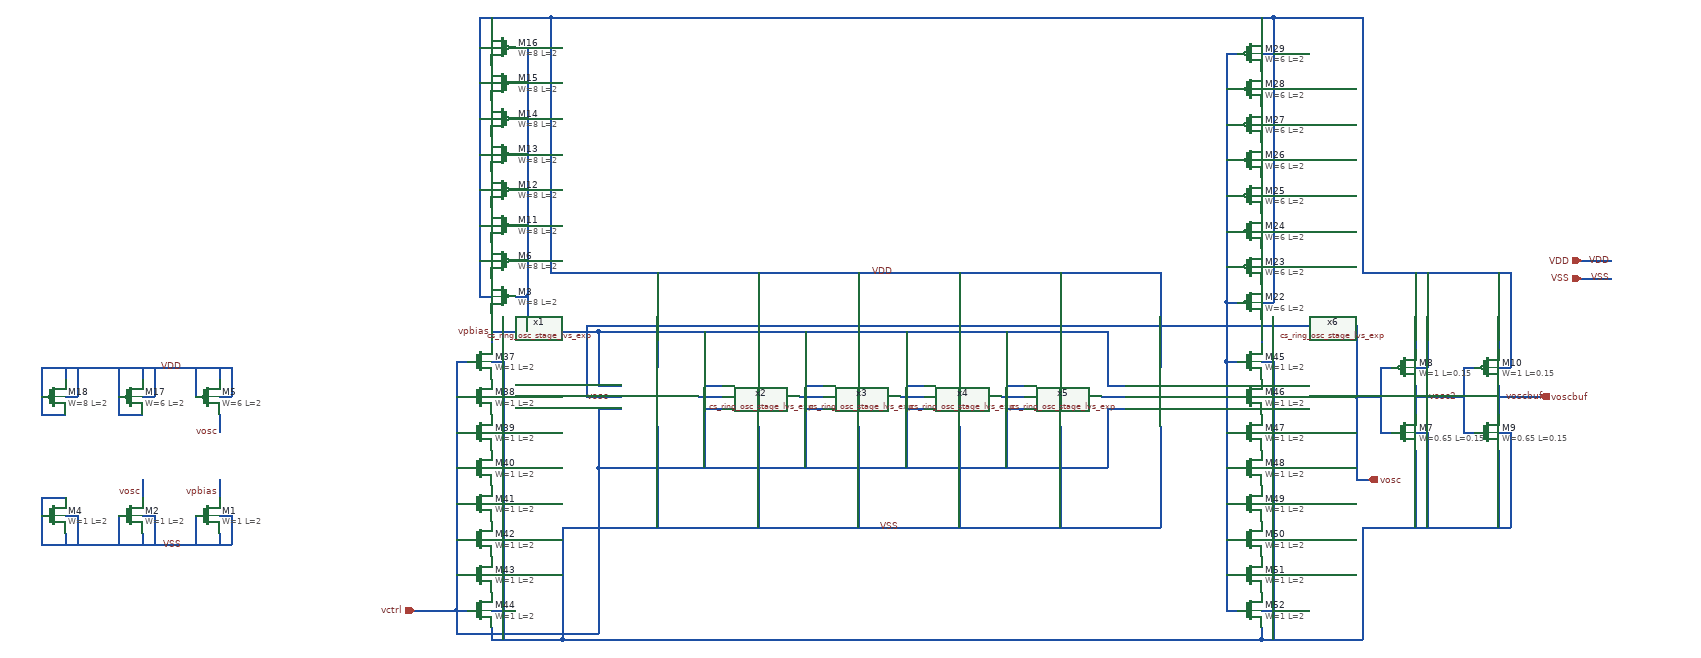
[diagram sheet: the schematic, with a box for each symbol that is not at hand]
v {xschem version=2.9.9 file_version=1.2 

* Copyright 2020 Stefan Frederik Schippers
* 
* Licensed under the Apache License, Version 2.0 (the "License");
* you may not use this file except in compliance with the License.
* You may obtain a copy of the License at
*
*     https://www.apache.org/licenses/LICENSE-2.0
*
* Unless required by applicable law or agreed to in writing, software
* distributed under the License is distributed on an "AS IS" BASIS,
* WITHOUT WARRANTIES OR CONDITIONS OF ANY KIND, either express or implied.
* See the License for the specific language governing permissions and
* limitations under the License.

}
G {}
K {}
V {}
S {}
E {}
N 100 -140 170 -140 { lab=vctrl}
N 350 -610 410 -610 { lab=vpbias}
N 410 -610 410 -520 { lab=vpbias}
N 410 -520 450 -520 { lab=vpbias}
N 410 -480 410 -380 { lab=vctrl}
N 410 -480 450 -480 { lab=vctrl}
N 580 -500 620 -500 { lab=#net1}
N 750 -500 790 -500 { lab=#net2}
N 920 -500 960 -500 { lab=#net3}
N 1090 -500 1130 -500 { lab=#net4}
N 1260 -500 1300 -500 { lab=#net5}
N 1430 -500 1470 -500 { lab=#net6}
N 410 -610 1270 -610 { lab=vpbias}
N 1270 -520 1300 -520 { lab=vpbias}
N 410 -380 1270 -380 { lab=vctrl}
N 1270 -480 1300 -480 { lab=vctrl}
N 1100 -520 1130 -520 { lab=vpbias}
N 1100 -480 1130 -480 { lab=vctrl}
N 930 -520 960 -520 { lab=vpbias}
N 930 -480 960 -480 { lab=vctrl}
N 760 -480 790 -480 { lab=vctrl}
N 760 -520 790 -520 { lab=vpbias}
N 590 -520 620 -520 { lab=vpbias}
N 590 -610 590 -520 { lab=vpbias}
N 590 -480 620 -480 { lab=vctrl}
N 590 -480 590 -380 { lab=vctrl}
N 390 -500 450 -500 { lab=vosc}
N 1690 -500 1690 -360 { lab=vosc}
N 1790 -550 1810 -550 { lab=VDD}
N 1790 -520 1790 -470 { lab=vosc2}
N 1790 -440 1810 -440 { lab=VSS}
N 1730 -550 1730 -490 { lab=vosc}
N 1730 -550 1750 -550 { lab=vosc}
N 1730 -490 1730 -440 { lab=vosc}
N 1730 -440 1750 -440 { lab=vosc}
N 1790 -710 1790 -580 { lab=VDD}
N 1810 -710 1810 -550 { lab=VDD}
N 1790 -410 1790 -280 { lab=VSS}
N 1810 -440 1810 -280 { lab=VSS}
N 1930 -550 1950 -550 { lab=VDD}
N 1930 -520 1930 -470 { lab=voscbuf}
N 1930 -440 1950 -440 { lab=VSS}
N 1870 -550 1870 -490 { lab=vosc2}
N 1870 -550 1890 -550 { lab=vosc2}
N 1870 -490 1870 -440 { lab=vosc2}
N 1870 -440 1890 -440 { lab=vosc2}
N 1930 -710 1930 -580 { lab=VDD}
N 1950 -710 1950 -550 { lab=VDD}
N 1930 -410 1930 -280 { lab=VSS}
N 1950 -440 1950 -280 { lab=VSS}
N 1790 -500 1870 -500 { lab=vosc2}
N 1690 -500 1730 -500 { lab=vosc}
N 510 -710 510 -550 { lab=VDD}
N 510 -450 510 -280 { lab=VSS}
N 760 -610 760 -520 { lab=vpbias}
N 760 -480 760 -380 { lab=vctrl}
N 680 -710 680 -550 { lab=VDD}
N 680 -450 680 -280 { lab=VSS}
N 930 -610 930 -520 { lab=vpbias}
N 930 -480 930 -380 { lab=vctrl}
N 850 -710 850 -550 { lab=VDD}
N 850 -450 850 -280 { lab=VSS}
N 1100 -610 1100 -520 { lab=vpbias}
N 1100 -480 1100 -380 { lab=vctrl}
N 1020 -710 1020 -550 { lab=VDD}
N 1020 -450 1020 -280 { lab=VSS}
N 1270 -610 1270 -520 { lab=vpbias}
N 1270 -480 1270 -380 { lab=vctrl}
N 1190 -710 1190 -550 { lab=VDD}
N 1190 -450 1190 -280 { lab=VSS}
N 1360 -710 1360 -550 { lab=VDD}
N 1360 -450 1360 -280 { lab=VSS}
N 2070 -730 2120 -730 { lab=VDD}
N 2070 -700 2120 -700 { lab=VSS}
N 1930 -500 2000 -500 { lab=voscbuf}
N 1690 -360 1710 -360 { lab=vosc}
N 210 -670 230 -670 { lab=VDD}
N 230 -1140 230 -1120 { lab=VDD}
N 210 -730 230 -730 { lab=VDD}
N 210 -790 230 -790 { lab=VDD}
N 210 -850 230 -850 { lab=VDD}
N 210 -910 230 -910 { lab=VDD}
N 210 -970 230 -970 { lab=VDD}
N 210 -1030 230 -1030 { lab=VDD}
N 210 -1090 230 -1090 { lab=VDD}
N 270 -1090 290 -1090 { lab=vpbias}
N 290 -1090 290 -670 { lab=vpbias}
N 270 -670 290 -670 { lab=vpbias}
N 270 -730 290 -730 { lab=vpbias}
N 270 -790 290 -790 { lab=vpbias}
N 270 -850 290 -850 { lab=vpbias}
N 270 -910 290 -910 { lab=vpbias}
N 270 -970 290 -970 { lab=vpbias}
N 270 -1030 290 -1030 { lab=vpbias}
N 230 -110 230 -90 { lab=VSS}
N 230 -560 250 -560 { lab=VSS}
N 230 -500 250 -500 { lab=VSS}
N 230 -440 250 -440 { lab=VSS}
N 230 -380 250 -380 { lab=VSS}
N 230 -320 250 -320 { lab=VSS}
N 230 -260 250 -260 { lab=VSS}
N 230 -200 250 -200 { lab=VSS}
N 230 -140 250 -140 { lab=VSS}
N 170 -560 190 -560 { lab=vctrl}
N 170 -560 170 -140 { lab=vctrl}
N 170 -140 190 -140 { lab=vctrl}
N 170 -200 190 -200 { lab=vctrl}
N 170 -260 190 -260 { lab=vctrl}
N 170 -320 190 -320 { lab=vctrl}
N 170 -380 190 -380 { lab=vctrl}
N 170 -440 190 -440 { lab=vctrl}
N 170 -500 190 -500 { lab=vctrl}
N 250 -560 250 -90 { lab=VSS}
N 230 -640 230 -590 { lab=vpbias}
N 230 -90 350 -90 { lab=VSS}
N 350 -280 350 -90 { lab=VSS}
N 410 -380 410 -100 { lab=vctrl}
N 170 -100 410 -100 { lab=vctrl}
N 170 -140 170 -100 { lab=vctrl}
N 230 -610 350 -610 { lab=vpbias}
N 210 -1140 210 -670 { lab=VDD}
N 210 -1140 330 -1140 { lab=VDD}
N 330 -1140 330 -710 { lab=VDD}
N 1530 -660 1550 -660 { lab=VDD}
N 1530 -720 1550 -720 { lab=VDD}
N 1530 -780 1550 -780 { lab=VDD}
N 1530 -840 1550 -840 { lab=VDD}
N 1530 -900 1550 -900 { lab=VDD}
N 1530 -960 1550 -960 { lab=VDD}
N 1530 -1020 1550 -1020 { lab=VDD}
N 1530 -1080 1550 -1080 { lab=VDD}
N 1530 -560 1550 -560 { lab=VSS}
N 1530 -500 1550 -500 { lab=VSS}
N 1530 -440 1550 -440 { lab=VSS}
N 1530 -380 1550 -380 { lab=VSS}
N 1530 -320 1550 -320 { lab=VSS}
N 1530 -260 1550 -260 { lab=VSS}
N 1530 -200 1550 -200 { lab=VSS}
N 1530 -140 1550 -140 { lab=VSS}
N 1530 -630 1530 -590 { lab=vosc}
N 1470 -560 1490 -560 { lab=#net6}
N 1470 -140 1490 -140 { lab=#net6}
N 1470 -200 1490 -200 { lab=#net6}
N 1470 -260 1490 -260 { lab=#net6}
N 1470 -320 1490 -320 { lab=#net6}
N 1470 -380 1490 -380 { lab=#net6}
N 1470 -440 1490 -440 { lab=#net6}
N 1470 -500 1490 -500 { lab=#net6}
N 1470 -1080 1490 -1080 { lab=#net6}
N 1470 -1080 1470 -660 { lab=#net6}
N 1470 -660 1490 -660 { lab=#net6}
N 1470 -720 1490 -720 { lab=#net6}
N 1470 -780 1490 -780 { lab=#net6}
N 1470 -840 1490 -840 { lab=#net6}
N 1470 -900 1490 -900 { lab=#net6}
N 1470 -960 1490 -960 { lab=#net6}
N 1470 -1020 1490 -1020 { lab=#net6}
N 1470 -560 1470 -140 { lab=#net6}
N 350 -90 1530 -90 { lab=VSS}
N 1530 -110 1530 -90 { lab=VSS}
N 1550 -560 1550 -90 { lab=VSS}
N 350 -280 1360 -280 { lab=VSS}
N 330 -710 1360 -710 { lab=VDD}
N 1530 -1130 1530 -1110 { lab=VDD}
N 1470 -660 1470 -560 { lab=#net6}
N 1690 -610 1690 -500 { lab=vosc}
N 330 -1140 1550 -1140 { lab=VDD}
N 1550 -1140 1550 -1120 { lab=VDD}
N 1550 -1120 1550 -660 { lab=VDD}
N 1530 -1140 1530 -1130 { lab=VDD}
N 1550 -1140 1700 -1140 { lab=VDD}
N 1700 -1140 1700 -710 { lab=VDD}
N 1700 -710 1950 -710 { lab=VDD}
N 1530 -90 1700 -90 { lab=VSS}
N 1700 -280 1700 -90 { lab=VSS}
N 1700 -280 1950 -280 { lab=VSS}
N 290 -670 290 -610 { lab=vpbias}
N 1690 -620 1690 -610 { lab=vosc}
N 1530 -620 1690 -620 { lab=vosc}
N 390 -620 1530 -620 { lab=vosc}
N 390 -620 390 -500 { lab=vosc}
N -230 -300 -210 -300 { lab=VSS}
N -210 -300 -210 -250 { lab=VSS}
N -230 -270 -230 -250 { lab=VSS}
N -270 -300 -270 -250 { lab=VSS}
N -230 -360 -230 -330 { lab=vpbias}
N -360 -300 -340 -300 { lab=VSS}
N -340 -300 -340 -250 { lab=VSS}
N -360 -270 -360 -250 { lab=VSS}
N -400 -300 -400 -250 { lab=VSS}
N -360 -360 -360 -330 { lab=vosc}
N -490 -300 -470 -300 { lab=VSS}
N -470 -300 -470 -250 { lab=VSS}
N -490 -270 -490 -250 { lab=VSS}
N -530 -300 -530 -250 { lab=VSS}
N -530 -250 -210 -250 { lab=VSS}
N -230 -470 -230 -440 { lab=vosc}
N -230 -550 -230 -530 { lab=#net7}
N -230 -500 -210 -500 { lab=#net7}
N -210 -550 -210 -500 { lab=#net7}
N -270 -550 -270 -500 { lab=#net7}
N -360 -550 -360 -530 { lab=#net7}
N -360 -500 -340 -500 { lab=#net7}
N -340 -550 -340 -500 { lab=#net7}
N -400 -550 -400 -500 { lab=#net7}
N -400 -470 -360 -470 { lab=#net7}
N -400 -500 -400 -470 { lab=#net7}
N -530 -330 -490 -330 { lab=VSS}
N -530 -330 -530 -300 { lab=VSS}
N -490 -550 -490 -530 { lab=#net7}
N -490 -500 -470 -500 { lab=#net7}
N -470 -550 -470 -500 { lab=#net7}
N -530 -550 -530 -500 { lab=#net7}
N -530 -470 -490 -470 { lab=#net7}
N -530 -500 -530 -470 { lab=#net7}
N -530 -550 -210 -550 { lab=#net7}
C {devices/title.sym} 160 -30 0 0 {name=l1 author="Nikhil Poole"}
C {devices/lab_wire.sym} 430 -500 0 0 {name=l9 sig_type=std_logic lab=vosc}
C {devices/lab_wire.sym} 230 -610 0 0 {name=l10 sig_type=std_logic lab=vpbias}
C {sky130_fd_pr/nfet_01v8.sym} 1770 -440 0 0 {name=M7
L=0.15
W=0.65
nf=1
mult=1
ad="'int((nf+1)/2) * W/nf * 0.29'" 
pd="'2*int((nf+1)/2) * (W/nf + 0.29)'"
as="'int((nf+2)/2) * W/nf * 0.29'" 
ps="'2*int((nf+2)/2) * (W/nf + 0.29)'"
nrd="'0.29 / W'" nrs="'0.29 / W'"
sa=0 sb=0 sd=0
model=nfet_01v8
spiceprefix=X
}
C {sky130_fd_pr/pfet_01v8_hvt.sym} 1770 -550 0 0 {name=M8
L=0.15
W=1
nf=1
mult=1
ad="'int((nf+1)/2) * W/nf * 0.29'" 
pd="'2*int((nf+1)/2) * (W/nf + 0.29)'"
as="'int((nf+2)/2) * W/nf * 0.29'" 
ps="'2*int((nf+2)/2) * (W/nf + 0.29)'"
nrd="'0.29 / W'" nrs="'0.29 / W'"
sa=0 sb=0 sd=0
model=pfet_01v8_hvt
spiceprefix=X
}
C {sky130_fd_pr/nfet_01v8.sym} 1910 -440 0 0 {name=M9
L=0.15
W=0.65
nf=1
mult=4
ad="'int((nf+1)/2) * W/nf * 0.29'" 
pd="'2*int((nf+1)/2) * (W/nf + 0.29)'"
as="'int((nf+2)/2) * W/nf * 0.29'" 
ps="'2*int((nf+2)/2) * (W/nf + 0.29)'"
nrd="'0.29 / W'" nrs="'0.29 / W'"
sa=0 sb=0 sd=0
model=nfet_01v8
spiceprefix=X
}
C {sky130_fd_pr/pfet_01v8_hvt.sym} 1910 -550 0 0 {name=M10
L=0.15
W=1
nf=1
mult=4
ad="'int((nf+1)/2) * W/nf * 0.29'" 
pd="'2*int((nf+1)/2) * (W/nf + 0.29)'"
as="'int((nf+2)/2) * W/nf * 0.29'" 
ps="'2*int((nf+2)/2) * (W/nf + 0.29)'"
nrd="'0.29 / W'" nrs="'0.29 / W'"
sa=0 sb=0 sd=0
model=pfet_01v8_hvt
spiceprefix=X
}
C {devices/lab_wire.sym} 1940 -500 0 1 {name=l11 sig_type=std_logic lab=voscbuf}
C {devices/lab_wire.sym} 1810 -500 0 1 {name=l14 sig_type=std_logic lab=vosc2}
C {devices/lab_wire.sym} 920 -280 0 0 {name=l2 sig_type=std_logic lab=VSS}
C {devices/lab_wire.sym} 910 -710 0 0 {name=l3 sig_type=std_logic lab=VDD}
C {devices/ipin.sym} 2070 -730 0 0 {name=p1 lab=VDD}
C {devices/ipin.sym} 2070 -700 0 0 {name=p2 lab=VSS}
C {devices/lab_wire.sym} 2120 -700 0 0 {name=l4 sig_type=std_logic lab=VSS}
C {devices/lab_wire.sym} 2120 -730 0 0 {name=l5 sig_type=std_logic lab=VDD}
C {devices/ipin.sym} 100 -140 0 0 {name=p3 lab=vctrl}
C {devices/opin.sym} 2000 -500 0 0 {name=p4 lab=voscbuf}
C {devices/opin.sym} 1710 -360 0 0 {name=p5 lab=vosc}
C {/home/users/nhpoole/ee272b/ee272b_mixed_signal_mmwave_accelerator/designs/cs_ring_osc_stage_lvs_exp.sym} 500 -500 0 0 {name=x1}
C {/home/users/nhpoole/ee272b/ee272b_mixed_signal_mmwave_accelerator/designs/cs_ring_osc_stage_lvs_exp.sym} 670 -500 0 0 {name=x2}
C {/home/users/nhpoole/ee272b/ee272b_mixed_signal_mmwave_accelerator/designs/cs_ring_osc_stage_lvs_exp.sym} 840 -500 0 0 {name=x3}
C {/home/users/nhpoole/ee272b/ee272b_mixed_signal_mmwave_accelerator/designs/cs_ring_osc_stage_lvs_exp.sym} 1010 -500 0 0 {name=x4}
C {/home/users/nhpoole/ee272b/ee272b_mixed_signal_mmwave_accelerator/designs/cs_ring_osc_stage_lvs_exp.sym} 1180 -500 0 0 {name=x5}
C {/home/users/nhpoole/ee272b/ee272b_mixed_signal_mmwave_accelerator/designs/cs_ring_osc_stage_lvs_exp.sym} 1350 -500 0 0 {name=x6}
C {sky130_fd_pr/pfet_01v8_hvt.sym} 250 -670 0 1 {name=M3
L=2
W=8
nf=1
mult=2
ad="'int((nf+1)/2) * W/nf * 0.29'" 
pd="'2*int((nf+1)/2) * (W/nf + 0.29)'"
as="'int((nf+2)/2) * W/nf * 0.29'" 
ps="'2*int((nf+2)/2) * (W/nf + 0.29)'"
nrd="'0.29 / W'" nrs="'0.29 / W'"
sa=0 sb=0 sd=0
model=pfet_01v8_hvt
spiceprefix=X
}
C {sky130_fd_pr/pfet_01v8_hvt.sym} 250 -730 0 1 {name=M6
L=2
W=8
nf=1
mult=2
ad="'int((nf+1)/2) * W/nf * 0.29'" 
pd="'2*int((nf+1)/2) * (W/nf + 0.29)'"
as="'int((nf+2)/2) * W/nf * 0.29'" 
ps="'2*int((nf+2)/2) * (W/nf + 0.29)'"
nrd="'0.29 / W'" nrs="'0.29 / W'"
sa=0 sb=0 sd=0
model=pfet_01v8_hvt
spiceprefix=X
}
C {sky130_fd_pr/pfet_01v8_hvt.sym} 250 -790 0 1 {name=M11
L=2
W=8
nf=1
mult=2
ad="'int((nf+1)/2) * W/nf * 0.29'" 
pd="'2*int((nf+1)/2) * (W/nf + 0.29)'"
as="'int((nf+2)/2) * W/nf * 0.29'" 
ps="'2*int((nf+2)/2) * (W/nf + 0.29)'"
nrd="'0.29 / W'" nrs="'0.29 / W'"
sa=0 sb=0 sd=0
model=pfet_01v8_hvt
spiceprefix=X
}
C {sky130_fd_pr/pfet_01v8_hvt.sym} 250 -850 0 1 {name=M12
L=2
W=8
nf=1
mult=2
ad="'int((nf+1)/2) * W/nf * 0.29'" 
pd="'2*int((nf+1)/2) * (W/nf + 0.29)'"
as="'int((nf+2)/2) * W/nf * 0.29'" 
ps="'2*int((nf+2)/2) * (W/nf + 0.29)'"
nrd="'0.29 / W'" nrs="'0.29 / W'"
sa=0 sb=0 sd=0
model=pfet_01v8_hvt
spiceprefix=X
}
C {sky130_fd_pr/pfet_01v8_hvt.sym} 250 -910 0 1 {name=M13
L=2
W=8
nf=1
mult=2
ad="'int((nf+1)/2) * W/nf * 0.29'" 
pd="'2*int((nf+1)/2) * (W/nf + 0.29)'"
as="'int((nf+2)/2) * W/nf * 0.29'" 
ps="'2*int((nf+2)/2) * (W/nf + 0.29)'"
nrd="'0.29 / W'" nrs="'0.29 / W'"
sa=0 sb=0 sd=0
model=pfet_01v8_hvt
spiceprefix=X
}
C {sky130_fd_pr/pfet_01v8_hvt.sym} 250 -970 0 1 {name=M14
L=2
W=8
nf=1
mult=2
ad="'int((nf+1)/2) * W/nf * 0.29'" 
pd="'2*int((nf+1)/2) * (W/nf + 0.29)'"
as="'int((nf+2)/2) * W/nf * 0.29'" 
ps="'2*int((nf+2)/2) * (W/nf + 0.29)'"
nrd="'0.29 / W'" nrs="'0.29 / W'"
sa=0 sb=0 sd=0
model=pfet_01v8_hvt
spiceprefix=X
}
C {sky130_fd_pr/pfet_01v8_hvt.sym} 250 -1030 0 1 {name=M15
L=2
W=8
nf=1
mult=2
ad="'int((nf+1)/2) * W/nf * 0.29'" 
pd="'2*int((nf+1)/2) * (W/nf + 0.29)'"
as="'int((nf+2)/2) * W/nf * 0.29'" 
ps="'2*int((nf+2)/2) * (W/nf + 0.29)'"
nrd="'0.29 / W'" nrs="'0.29 / W'"
sa=0 sb=0 sd=0
model=pfet_01v8_hvt
spiceprefix=X
}
C {sky130_fd_pr/pfet_01v8_hvt.sym} 250 -1090 0 1 {name=M16
L=2
W=8
nf=1
mult=2
ad="'int((nf+1)/2) * W/nf * 0.29'" 
pd="'2*int((nf+1)/2) * (W/nf + 0.29)'"
as="'int((nf+2)/2) * W/nf * 0.29'" 
ps="'2*int((nf+2)/2) * (W/nf + 0.29)'"
nrd="'0.29 / W'" nrs="'0.29 / W'"
sa=0 sb=0 sd=0
model=pfet_01v8_hvt
spiceprefix=X
}
C {sky130_fd_pr/nfet_01v8.sym} 210 -560 0 0 {name=M37
L=2
W=1
nf=1 
mult=1
ad="'int((nf+1)/2) * W/nf * 0.29'" 
pd="'2*int((nf+1)/2) * (W/nf + 0.29)'"
as="'int((nf+2)/2) * W/nf * 0.29'" 
ps="'2*int((nf+2)/2) * (W/nf + 0.29)'"
nrd="'0.29 / W'" nrs="'0.29 / W'"
sa=0 sb=0 sd=0
model=nfet_01v8
spiceprefix=X
}
C {sky130_fd_pr/nfet_01v8.sym} 210 -500 0 0 {name=M38
L=2
W=1
nf=1 
mult=1
ad="'int((nf+1)/2) * W/nf * 0.29'" 
pd="'2*int((nf+1)/2) * (W/nf + 0.29)'"
as="'int((nf+2)/2) * W/nf * 0.29'" 
ps="'2*int((nf+2)/2) * (W/nf + 0.29)'"
nrd="'0.29 / W'" nrs="'0.29 / W'"
sa=0 sb=0 sd=0
model=nfet_01v8
spiceprefix=X
}
C {sky130_fd_pr/nfet_01v8.sym} 210 -440 0 0 {name=M39
L=2
W=1
nf=1 
mult=1
ad="'int((nf+1)/2) * W/nf * 0.29'" 
pd="'2*int((nf+1)/2) * (W/nf + 0.29)'"
as="'int((nf+2)/2) * W/nf * 0.29'" 
ps="'2*int((nf+2)/2) * (W/nf + 0.29)'"
nrd="'0.29 / W'" nrs="'0.29 / W'"
sa=0 sb=0 sd=0
model=nfet_01v8
spiceprefix=X
}
C {sky130_fd_pr/nfet_01v8.sym} 210 -380 0 0 {name=M40
L=2
W=1
nf=1 
mult=1
ad="'int((nf+1)/2) * W/nf * 0.29'" 
pd="'2*int((nf+1)/2) * (W/nf + 0.29)'"
as="'int((nf+2)/2) * W/nf * 0.29'" 
ps="'2*int((nf+2)/2) * (W/nf + 0.29)'"
nrd="'0.29 / W'" nrs="'0.29 / W'"
sa=0 sb=0 sd=0
model=nfet_01v8
spiceprefix=X
}
C {sky130_fd_pr/nfet_01v8.sym} 210 -320 0 0 {name=M41
L=2
W=1
nf=1 
mult=1
ad="'int((nf+1)/2) * W/nf * 0.29'" 
pd="'2*int((nf+1)/2) * (W/nf + 0.29)'"
as="'int((nf+2)/2) * W/nf * 0.29'" 
ps="'2*int((nf+2)/2) * (W/nf + 0.29)'"
nrd="'0.29 / W'" nrs="'0.29 / W'"
sa=0 sb=0 sd=0
model=nfet_01v8
spiceprefix=X
}
C {sky130_fd_pr/nfet_01v8.sym} 210 -260 0 0 {name=M42
L=2
W=1
nf=1 
mult=1
ad="'int((nf+1)/2) * W/nf * 0.29'" 
pd="'2*int((nf+1)/2) * (W/nf + 0.29)'"
as="'int((nf+2)/2) * W/nf * 0.29'" 
ps="'2*int((nf+2)/2) * (W/nf + 0.29)'"
nrd="'0.29 / W'" nrs="'0.29 / W'"
sa=0 sb=0 sd=0
model=nfet_01v8
spiceprefix=X
}
C {sky130_fd_pr/nfet_01v8.sym} 210 -200 0 0 {name=M43
L=2
W=1
nf=1 
mult=1
ad="'int((nf+1)/2) * W/nf * 0.29'" 
pd="'2*int((nf+1)/2) * (W/nf + 0.29)'"
as="'int((nf+2)/2) * W/nf * 0.29'" 
ps="'2*int((nf+2)/2) * (W/nf + 0.29)'"
nrd="'0.29 / W'" nrs="'0.29 / W'"
sa=0 sb=0 sd=0
model=nfet_01v8
spiceprefix=X
}
C {sky130_fd_pr/nfet_01v8.sym} 210 -140 0 0 {name=M44
L=2
W=1
nf=1 
mult=1
ad="'int((nf+1)/2) * W/nf * 0.29'" 
pd="'2*int((nf+1)/2) * (W/nf + 0.29)'"
as="'int((nf+2)/2) * W/nf * 0.29'" 
ps="'2*int((nf+2)/2) * (W/nf + 0.29)'"
nrd="'0.29 / W'" nrs="'0.29 / W'"
sa=0 sb=0 sd=0
model=nfet_01v8
spiceprefix=X
}
C {sky130_fd_pr/pfet_01v8_hvt.sym} 1510 -660 0 0 {name=M22
L=2
W=6
nf=1
mult=1
ad="'int((nf+1)/2) * W/nf * 0.29'" 
pd="'2*int((nf+1)/2) * (W/nf + 0.29)'"
as="'int((nf+2)/2) * W/nf * 0.29'" 
ps="'2*int((nf+2)/2) * (W/nf + 0.29)'"
nrd="'0.29 / W'" nrs="'0.29 / W'"
sa=0 sb=0 sd=0
model=pfet_01v8_hvt
spiceprefix=X
}
C {sky130_fd_pr/pfet_01v8_hvt.sym} 1510 -720 0 0 {name=M23
L=2
W=6
nf=1
mult=1
ad="'int((nf+1)/2) * W/nf * 0.29'" 
pd="'2*int((nf+1)/2) * (W/nf + 0.29)'"
as="'int((nf+2)/2) * W/nf * 0.29'" 
ps="'2*int((nf+2)/2) * (W/nf + 0.29)'"
nrd="'0.29 / W'" nrs="'0.29 / W'"
sa=0 sb=0 sd=0
model=pfet_01v8_hvt
spiceprefix=X
}
C {sky130_fd_pr/pfet_01v8_hvt.sym} 1510 -780 0 0 {name=M24
L=2
W=6
nf=1
mult=1
ad="'int((nf+1)/2) * W/nf * 0.29'" 
pd="'2*int((nf+1)/2) * (W/nf + 0.29)'"
as="'int((nf+2)/2) * W/nf * 0.29'" 
ps="'2*int((nf+2)/2) * (W/nf + 0.29)'"
nrd="'0.29 / W'" nrs="'0.29 / W'"
sa=0 sb=0 sd=0
model=pfet_01v8_hvt
spiceprefix=X
}
C {sky130_fd_pr/pfet_01v8_hvt.sym} 1510 -840 0 0 {name=M25
L=2
W=6
nf=1
mult=1
ad="'int((nf+1)/2) * W/nf * 0.29'" 
pd="'2*int((nf+1)/2) * (W/nf + 0.29)'"
as="'int((nf+2)/2) * W/nf * 0.29'" 
ps="'2*int((nf+2)/2) * (W/nf + 0.29)'"
nrd="'0.29 / W'" nrs="'0.29 / W'"
sa=0 sb=0 sd=0
model=pfet_01v8_hvt
spiceprefix=X
}
C {sky130_fd_pr/pfet_01v8_hvt.sym} 1510 -900 0 0 {name=M26
L=2
W=6
nf=1
mult=1
ad="'int((nf+1)/2) * W/nf * 0.29'" 
pd="'2*int((nf+1)/2) * (W/nf + 0.29)'"
as="'int((nf+2)/2) * W/nf * 0.29'" 
ps="'2*int((nf+2)/2) * (W/nf + 0.29)'"
nrd="'0.29 / W'" nrs="'0.29 / W'"
sa=0 sb=0 sd=0
model=pfet_01v8_hvt
spiceprefix=X
}
C {sky130_fd_pr/pfet_01v8_hvt.sym} 1510 -960 0 0 {name=M27
L=2
W=6
nf=1
mult=1
ad="'int((nf+1)/2) * W/nf * 0.29'" 
pd="'2*int((nf+1)/2) * (W/nf + 0.29)'"
as="'int((nf+2)/2) * W/nf * 0.29'" 
ps="'2*int((nf+2)/2) * (W/nf + 0.29)'"
nrd="'0.29 / W'" nrs="'0.29 / W'"
sa=0 sb=0 sd=0
model=pfet_01v8_hvt
spiceprefix=X
}
C {sky130_fd_pr/pfet_01v8_hvt.sym} 1510 -1020 0 0 {name=M28
L=2
W=6
nf=1
mult=1
ad="'int((nf+1)/2) * W/nf * 0.29'" 
pd="'2*int((nf+1)/2) * (W/nf + 0.29)'"
as="'int((nf+2)/2) * W/nf * 0.29'" 
ps="'2*int((nf+2)/2) * (W/nf + 0.29)'"
nrd="'0.29 / W'" nrs="'0.29 / W'"
sa=0 sb=0 sd=0
model=pfet_01v8_hvt
spiceprefix=X
}
C {sky130_fd_pr/pfet_01v8_hvt.sym} 1510 -1080 0 0 {name=M29
L=2
W=6
nf=1
mult=1
ad="'int((nf+1)/2) * W/nf * 0.29'" 
pd="'2*int((nf+1)/2) * (W/nf + 0.29)'"
as="'int((nf+2)/2) * W/nf * 0.29'" 
ps="'2*int((nf+2)/2) * (W/nf + 0.29)'"
nrd="'0.29 / W'" nrs="'0.29 / W'"
sa=0 sb=0 sd=0
model=pfet_01v8_hvt
spiceprefix=X
}
C {sky130_fd_pr/nfet_01v8.sym} 1510 -560 0 0 {name=M45
L=2
W=1
nf=1 
mult=1
ad="'int((nf+1)/2) * W/nf * 0.29'" 
pd="'2*int((nf+1)/2) * (W/nf + 0.29)'"
as="'int((nf+2)/2) * W/nf * 0.29'" 
ps="'2*int((nf+2)/2) * (W/nf + 0.29)'"
nrd="'0.29 / W'" nrs="'0.29 / W'"
sa=0 sb=0 sd=0
model=nfet_01v8
spiceprefix=X
}
C {sky130_fd_pr/nfet_01v8.sym} 1510 -500 0 0 {name=M46
L=2
W=1
nf=1 
mult=1
ad="'int((nf+1)/2) * W/nf * 0.29'" 
pd="'2*int((nf+1)/2) * (W/nf + 0.29)'"
as="'int((nf+2)/2) * W/nf * 0.29'" 
ps="'2*int((nf+2)/2) * (W/nf + 0.29)'"
nrd="'0.29 / W'" nrs="'0.29 / W'"
sa=0 sb=0 sd=0
model=nfet_01v8
spiceprefix=X
}
C {sky130_fd_pr/nfet_01v8.sym} 1510 -440 0 0 {name=M47
L=2
W=1
nf=1 
mult=1
ad="'int((nf+1)/2) * W/nf * 0.29'" 
pd="'2*int((nf+1)/2) * (W/nf + 0.29)'"
as="'int((nf+2)/2) * W/nf * 0.29'" 
ps="'2*int((nf+2)/2) * (W/nf + 0.29)'"
nrd="'0.29 / W'" nrs="'0.29 / W'"
sa=0 sb=0 sd=0
model=nfet_01v8
spiceprefix=X
}
C {sky130_fd_pr/nfet_01v8.sym} 1510 -380 0 0 {name=M48
L=2
W=1
nf=1 
mult=1
ad="'int((nf+1)/2) * W/nf * 0.29'" 
pd="'2*int((nf+1)/2) * (W/nf + 0.29)'"
as="'int((nf+2)/2) * W/nf * 0.29'" 
ps="'2*int((nf+2)/2) * (W/nf + 0.29)'"
nrd="'0.29 / W'" nrs="'0.29 / W'"
sa=0 sb=0 sd=0
model=nfet_01v8
spiceprefix=X
}
C {sky130_fd_pr/nfet_01v8.sym} 1510 -320 0 0 {name=M49
L=2
W=1
nf=1 
mult=1
ad="'int((nf+1)/2) * W/nf * 0.29'" 
pd="'2*int((nf+1)/2) * (W/nf + 0.29)'"
as="'int((nf+2)/2) * W/nf * 0.29'" 
ps="'2*int((nf+2)/2) * (W/nf + 0.29)'"
nrd="'0.29 / W'" nrs="'0.29 / W'"
sa=0 sb=0 sd=0
model=nfet_01v8
spiceprefix=X
}
C {sky130_fd_pr/nfet_01v8.sym} 1510 -260 0 0 {name=M50
L=2
W=1
nf=1 
mult=1
ad="'int((nf+1)/2) * W/nf * 0.29'" 
pd="'2*int((nf+1)/2) * (W/nf + 0.29)'"
as="'int((nf+2)/2) * W/nf * 0.29'" 
ps="'2*int((nf+2)/2) * (W/nf + 0.29)'"
nrd="'0.29 / W'" nrs="'0.29 / W'"
sa=0 sb=0 sd=0
model=nfet_01v8
spiceprefix=X
}
C {sky130_fd_pr/nfet_01v8.sym} 1510 -200 0 0 {name=M51
L=2
W=1
nf=1 
mult=1
ad="'int((nf+1)/2) * W/nf * 0.29'" 
pd="'2*int((nf+1)/2) * (W/nf + 0.29)'"
as="'int((nf+2)/2) * W/nf * 0.29'" 
ps="'2*int((nf+2)/2) * (W/nf + 0.29)'"
nrd="'0.29 / W'" nrs="'0.29 / W'"
sa=0 sb=0 sd=0
model=nfet_01v8
spiceprefix=X
}
C {sky130_fd_pr/nfet_01v8.sym} 1510 -140 0 0 {name=M52
L=2
W=1
nf=1 
mult=1
ad="'int((nf+1)/2) * W/nf * 0.29'" 
pd="'2*int((nf+1)/2) * (W/nf + 0.29)'"
as="'int((nf+2)/2) * W/nf * 0.29'" 
ps="'2*int((nf+2)/2) * (W/nf + 0.29)'"
nrd="'0.29 / W'" nrs="'0.29 / W'"
sa=0 sb=0 sd=0
model=nfet_01v8
spiceprefix=X
}
C {sky130_fd_pr/nfet_01v8.sym} -250 -300 0 0 {name=M1
L=2
W=1
nf=1 
mult=1
ad="'int((nf+1)/2) * W/nf * 0.29'" 
pd="'2*int((nf+1)/2) * (W/nf + 0.29)'"
as="'int((nf+2)/2) * W/nf * 0.29'" 
ps="'2*int((nf+2)/2) * (W/nf + 0.29)'"
nrd="'0.29 / W'" nrs="'0.29 / W'"
sa=0 sb=0 sd=0
model=nfet_01v8
spiceprefix=X
}
C {devices/lab_wire.sym} -230 -340 0 0 {name=l6 sig_type=std_logic lab=vpbias}
C {sky130_fd_pr/nfet_01v8.sym} -380 -300 0 0 {name=M2
L=2
W=1
nf=1 
mult=1
ad="'int((nf+1)/2) * W/nf * 0.29'" 
pd="'2*int((nf+1)/2) * (W/nf + 0.29)'"
as="'int((nf+2)/2) * W/nf * 0.29'" 
ps="'2*int((nf+2)/2) * (W/nf + 0.29)'"
nrd="'0.29 / W'" nrs="'0.29 / W'"
sa=0 sb=0 sd=0
model=nfet_01v8
spiceprefix=X
}
C {devices/lab_wire.sym} -360 -340 0 0 {name=l7 sig_type=std_logic lab=vosc}
C {sky130_fd_pr/nfet_01v8.sym} -510 -300 0 0 {name=M4
L=2
W=1
nf=1 
mult=2
ad="'int((nf+1)/2) * W/nf * 0.29'" 
pd="'2*int((nf+1)/2) * (W/nf + 0.29)'"
as="'int((nf+2)/2) * W/nf * 0.29'" 
ps="'2*int((nf+2)/2) * (W/nf + 0.29)'"
nrd="'0.29 / W'" nrs="'0.29 / W'"
sa=0 sb=0 sd=0
model=nfet_01v8
spiceprefix=X
}
C {devices/lab_wire.sym} -290 -250 0 0 {name=l12 sig_type=std_logic lab=VSS}
C {sky130_fd_pr/pfet_01v8_hvt.sym} -250 -500 0 0 {name=M5
L=2
W=6
nf=1
mult=1
ad="'int((nf+1)/2) * W/nf * 0.29'" 
pd="'2*int((nf+1)/2) * (W/nf + 0.29)'"
as="'int((nf+2)/2) * W/nf * 0.29'" 
ps="'2*int((nf+2)/2) * (W/nf + 0.29)'"
nrd="'0.29 / W'" nrs="'0.29 / W'"
sa=0 sb=0 sd=0
model=pfet_01v8_hvt
spiceprefix=X
}
C {devices/lab_wire.sym} -230 -440 0 0 {name=l13 sig_type=std_logic lab=vosc}
C {sky130_fd_pr/pfet_01v8_hvt.sym} -380 -500 0 0 {name=M17
L=2
W=6
nf=1
mult=1
ad="'int((nf+1)/2) * W/nf * 0.29'" 
pd="'2*int((nf+1)/2) * (W/nf + 0.29)'"
as="'int((nf+2)/2) * W/nf * 0.29'" 
ps="'2*int((nf+2)/2) * (W/nf + 0.29)'"
nrd="'0.29 / W'" nrs="'0.29 / W'"
sa=0 sb=0 sd=0
model=pfet_01v8_hvt
spiceprefix=X
}
C {sky130_fd_pr/pfet_01v8_hvt.sym} -510 -500 0 0 {name=M18
L=2
W=8
nf=1
mult=2
ad="'int((nf+1)/2) * W/nf * 0.29'" 
pd="'2*int((nf+1)/2) * (W/nf + 0.29)'"
as="'int((nf+2)/2) * W/nf * 0.29'" 
ps="'2*int((nf+2)/2) * (W/nf + 0.29)'"
nrd="'0.29 / W'" nrs="'0.29 / W'"
sa=0 sb=0 sd=0
model=pfet_01v8_hvt
spiceprefix=X
}
C {devices/lab_wire.sym} -290 -550 0 0 {name=l8 sig_type=std_logic lab=VDD}
